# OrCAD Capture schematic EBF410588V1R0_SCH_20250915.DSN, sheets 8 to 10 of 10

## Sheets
8 10 HDMI2.1/DSI PORT: size A3; note: HDMI2.1/DSI PORT
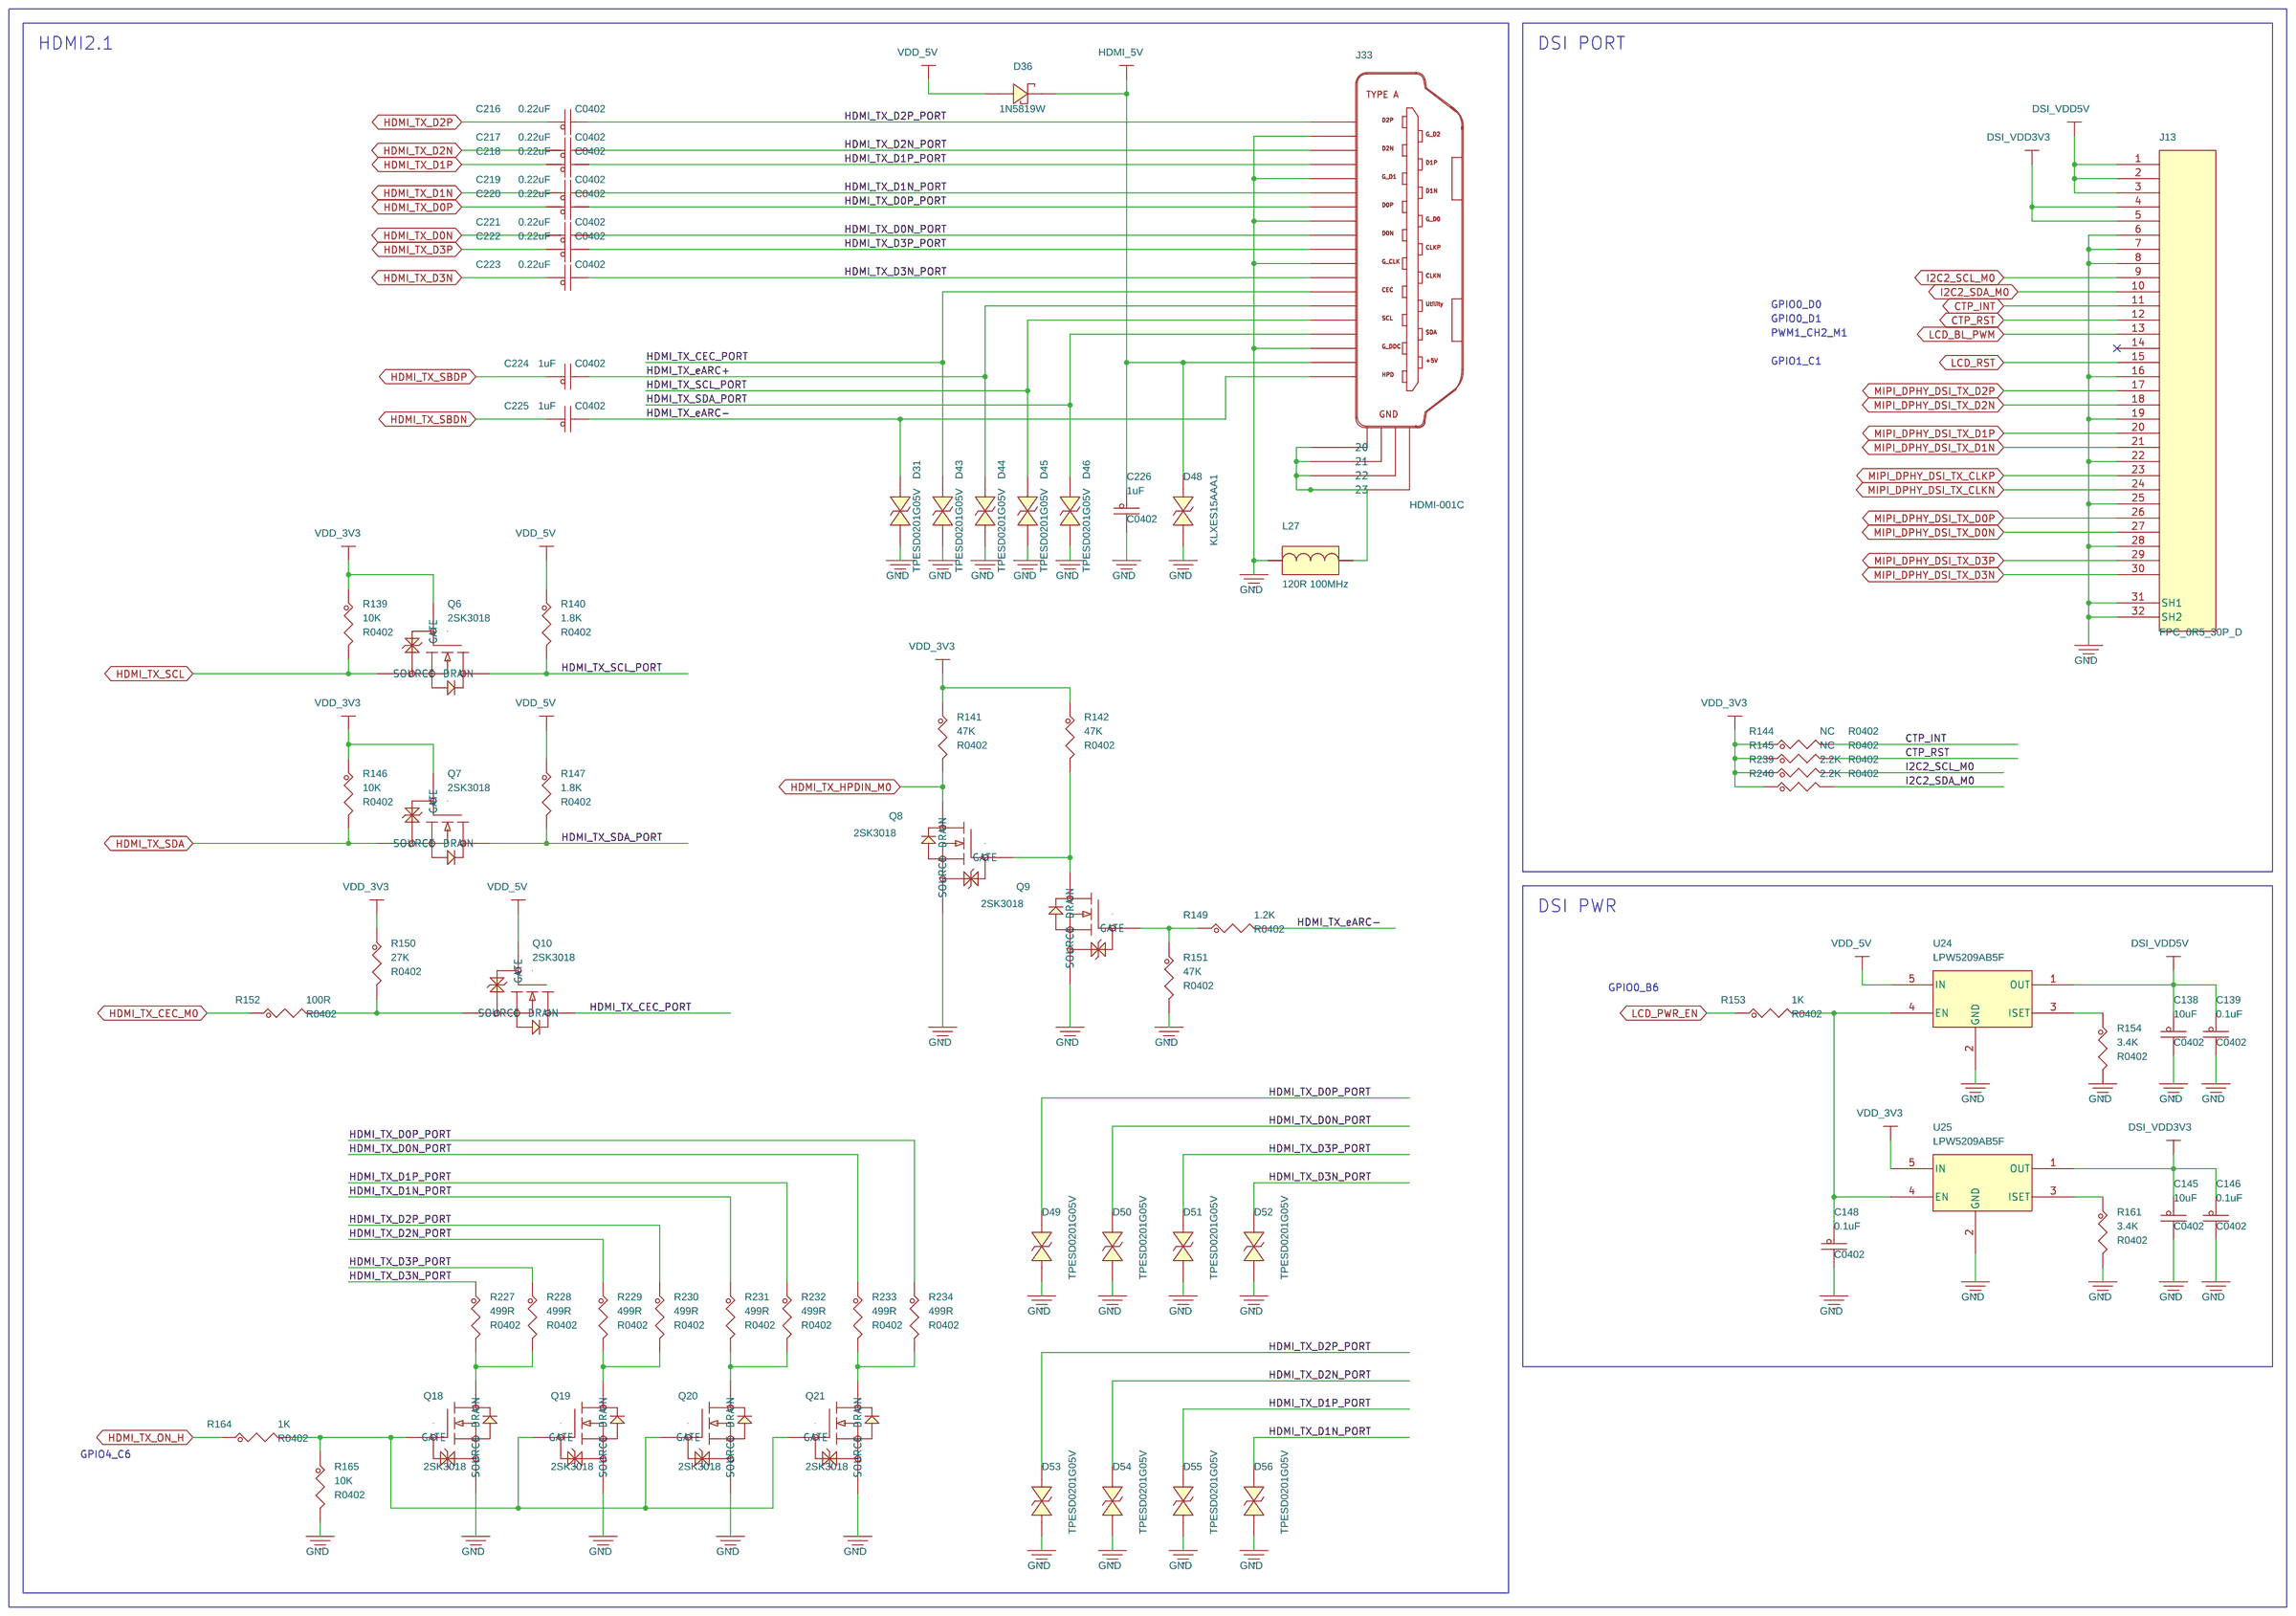
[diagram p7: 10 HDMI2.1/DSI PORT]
9 05 SD Card/RTC/KEY/IR: size A4; note: SD Card/RTC/KEY/IR
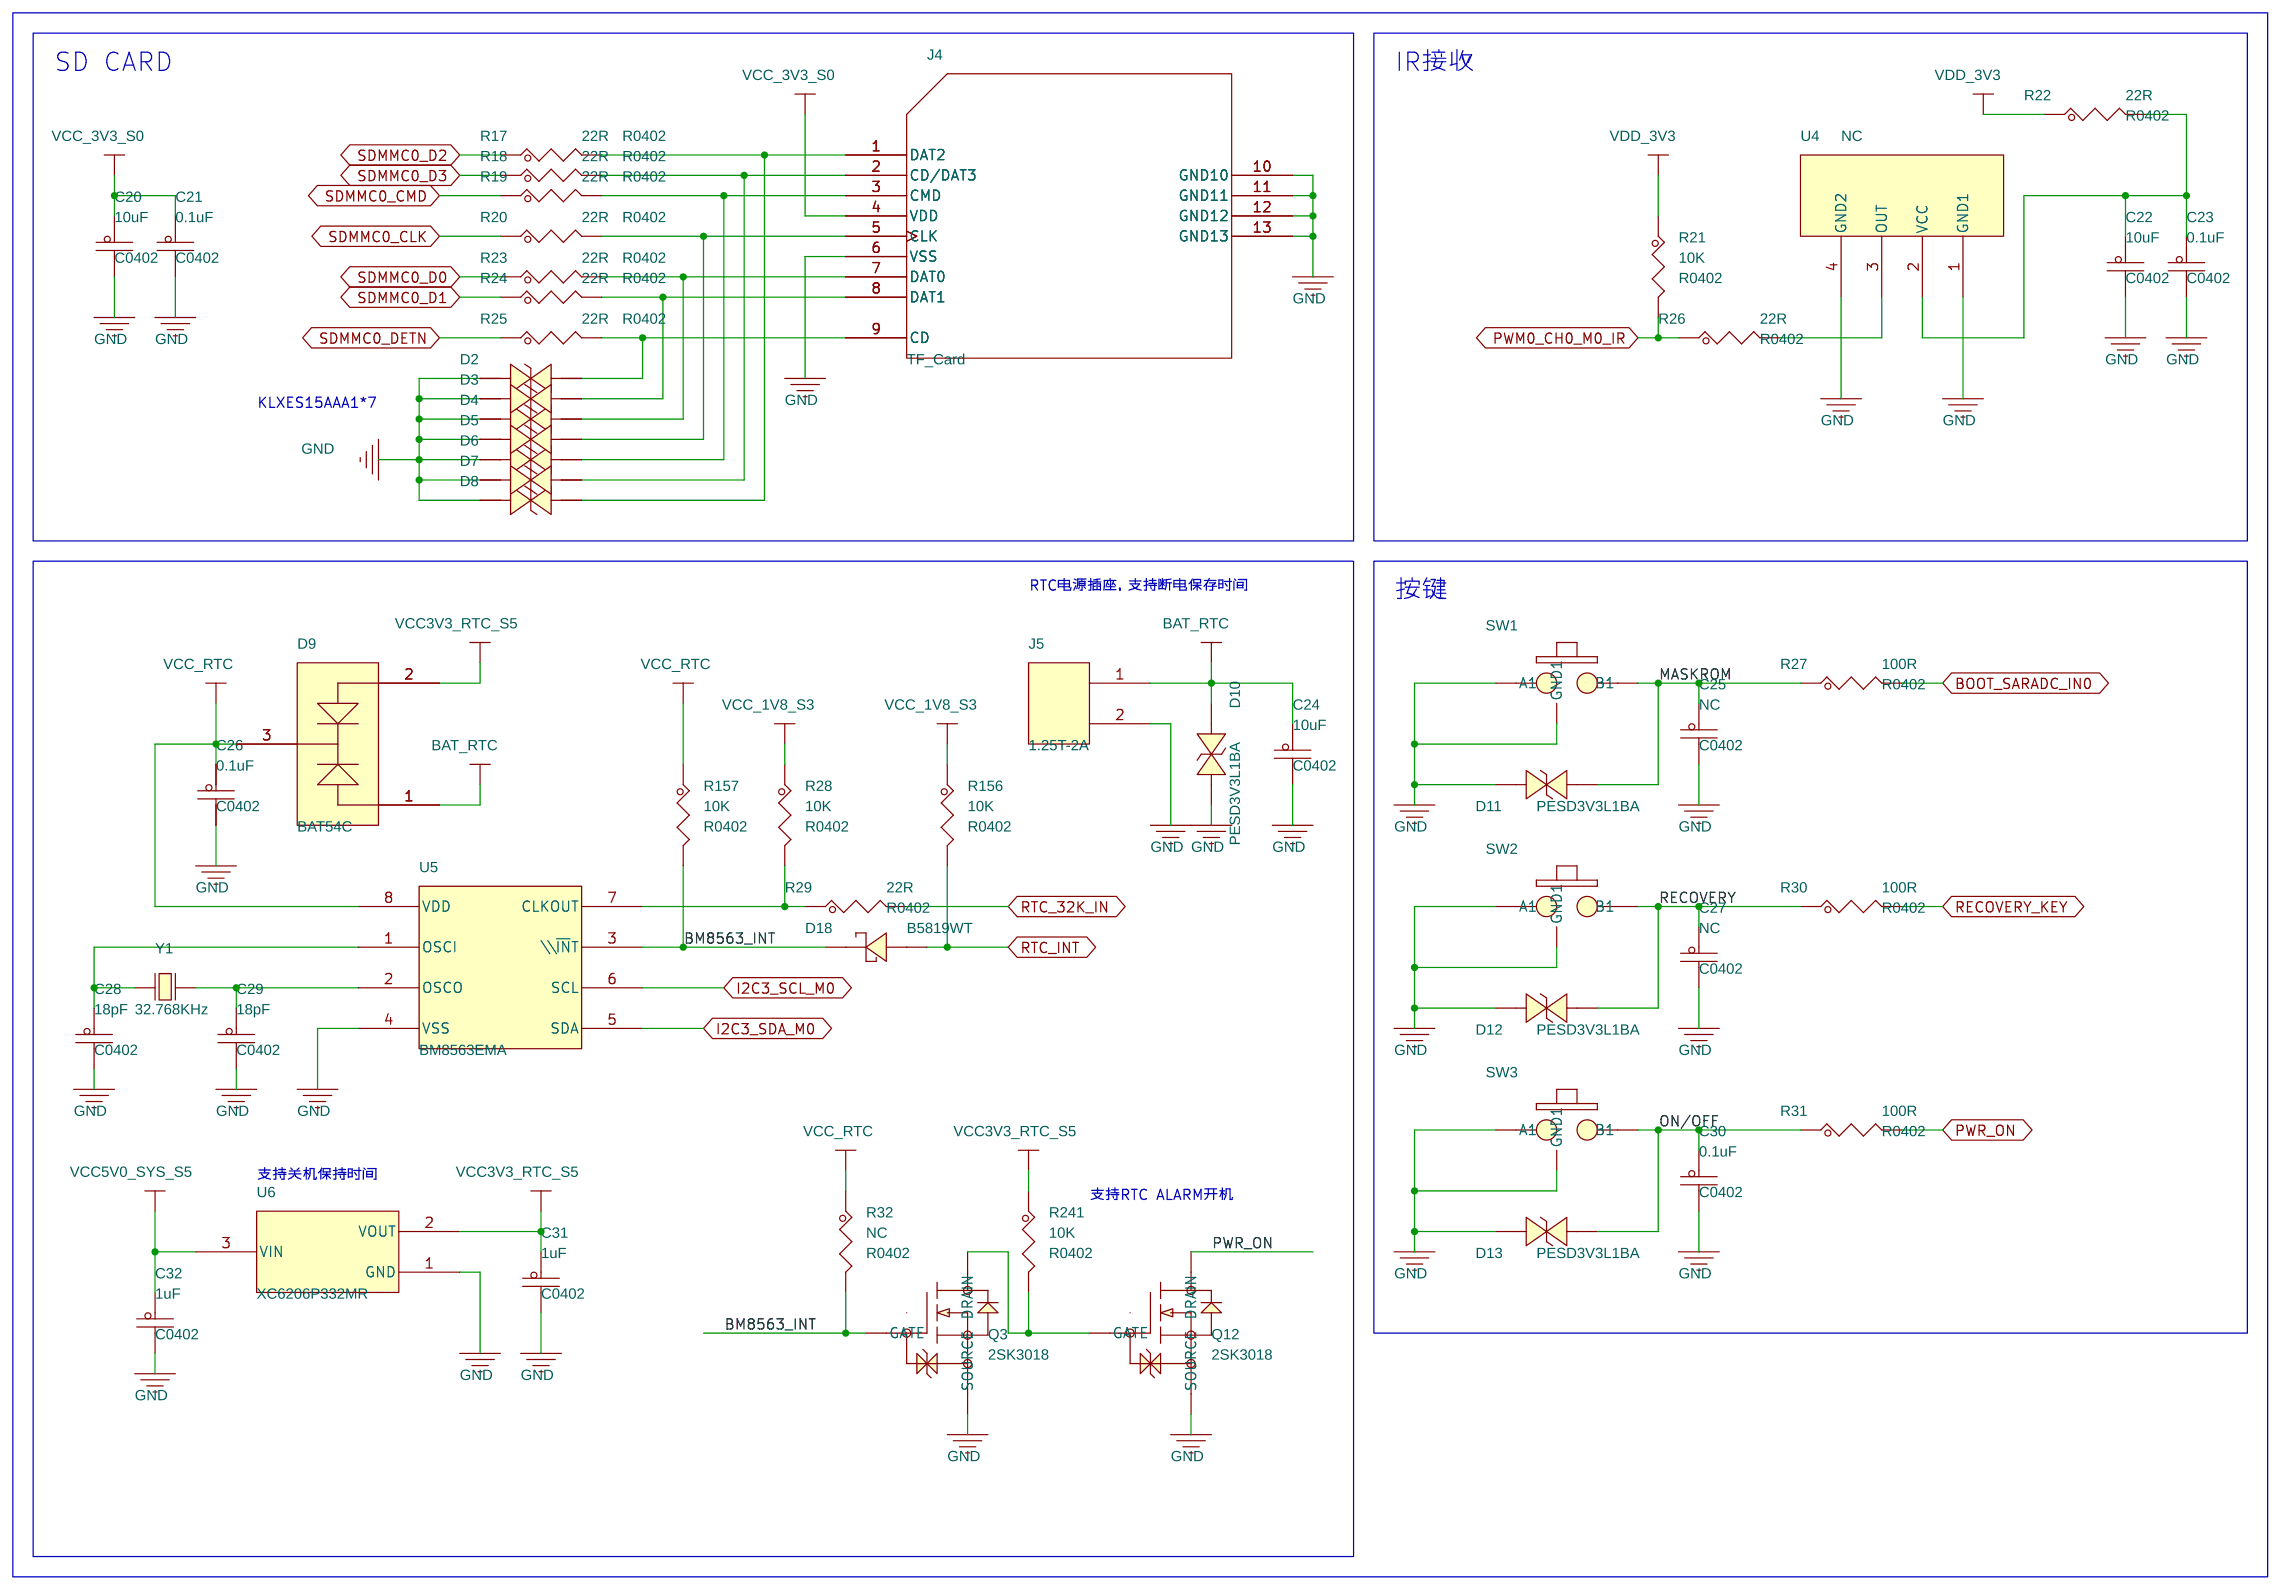
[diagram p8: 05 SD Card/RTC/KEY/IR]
10 09 USB3.0/USB2.0/TYPEC: size A3; note: USB3.0/USB2.0/TYPEC

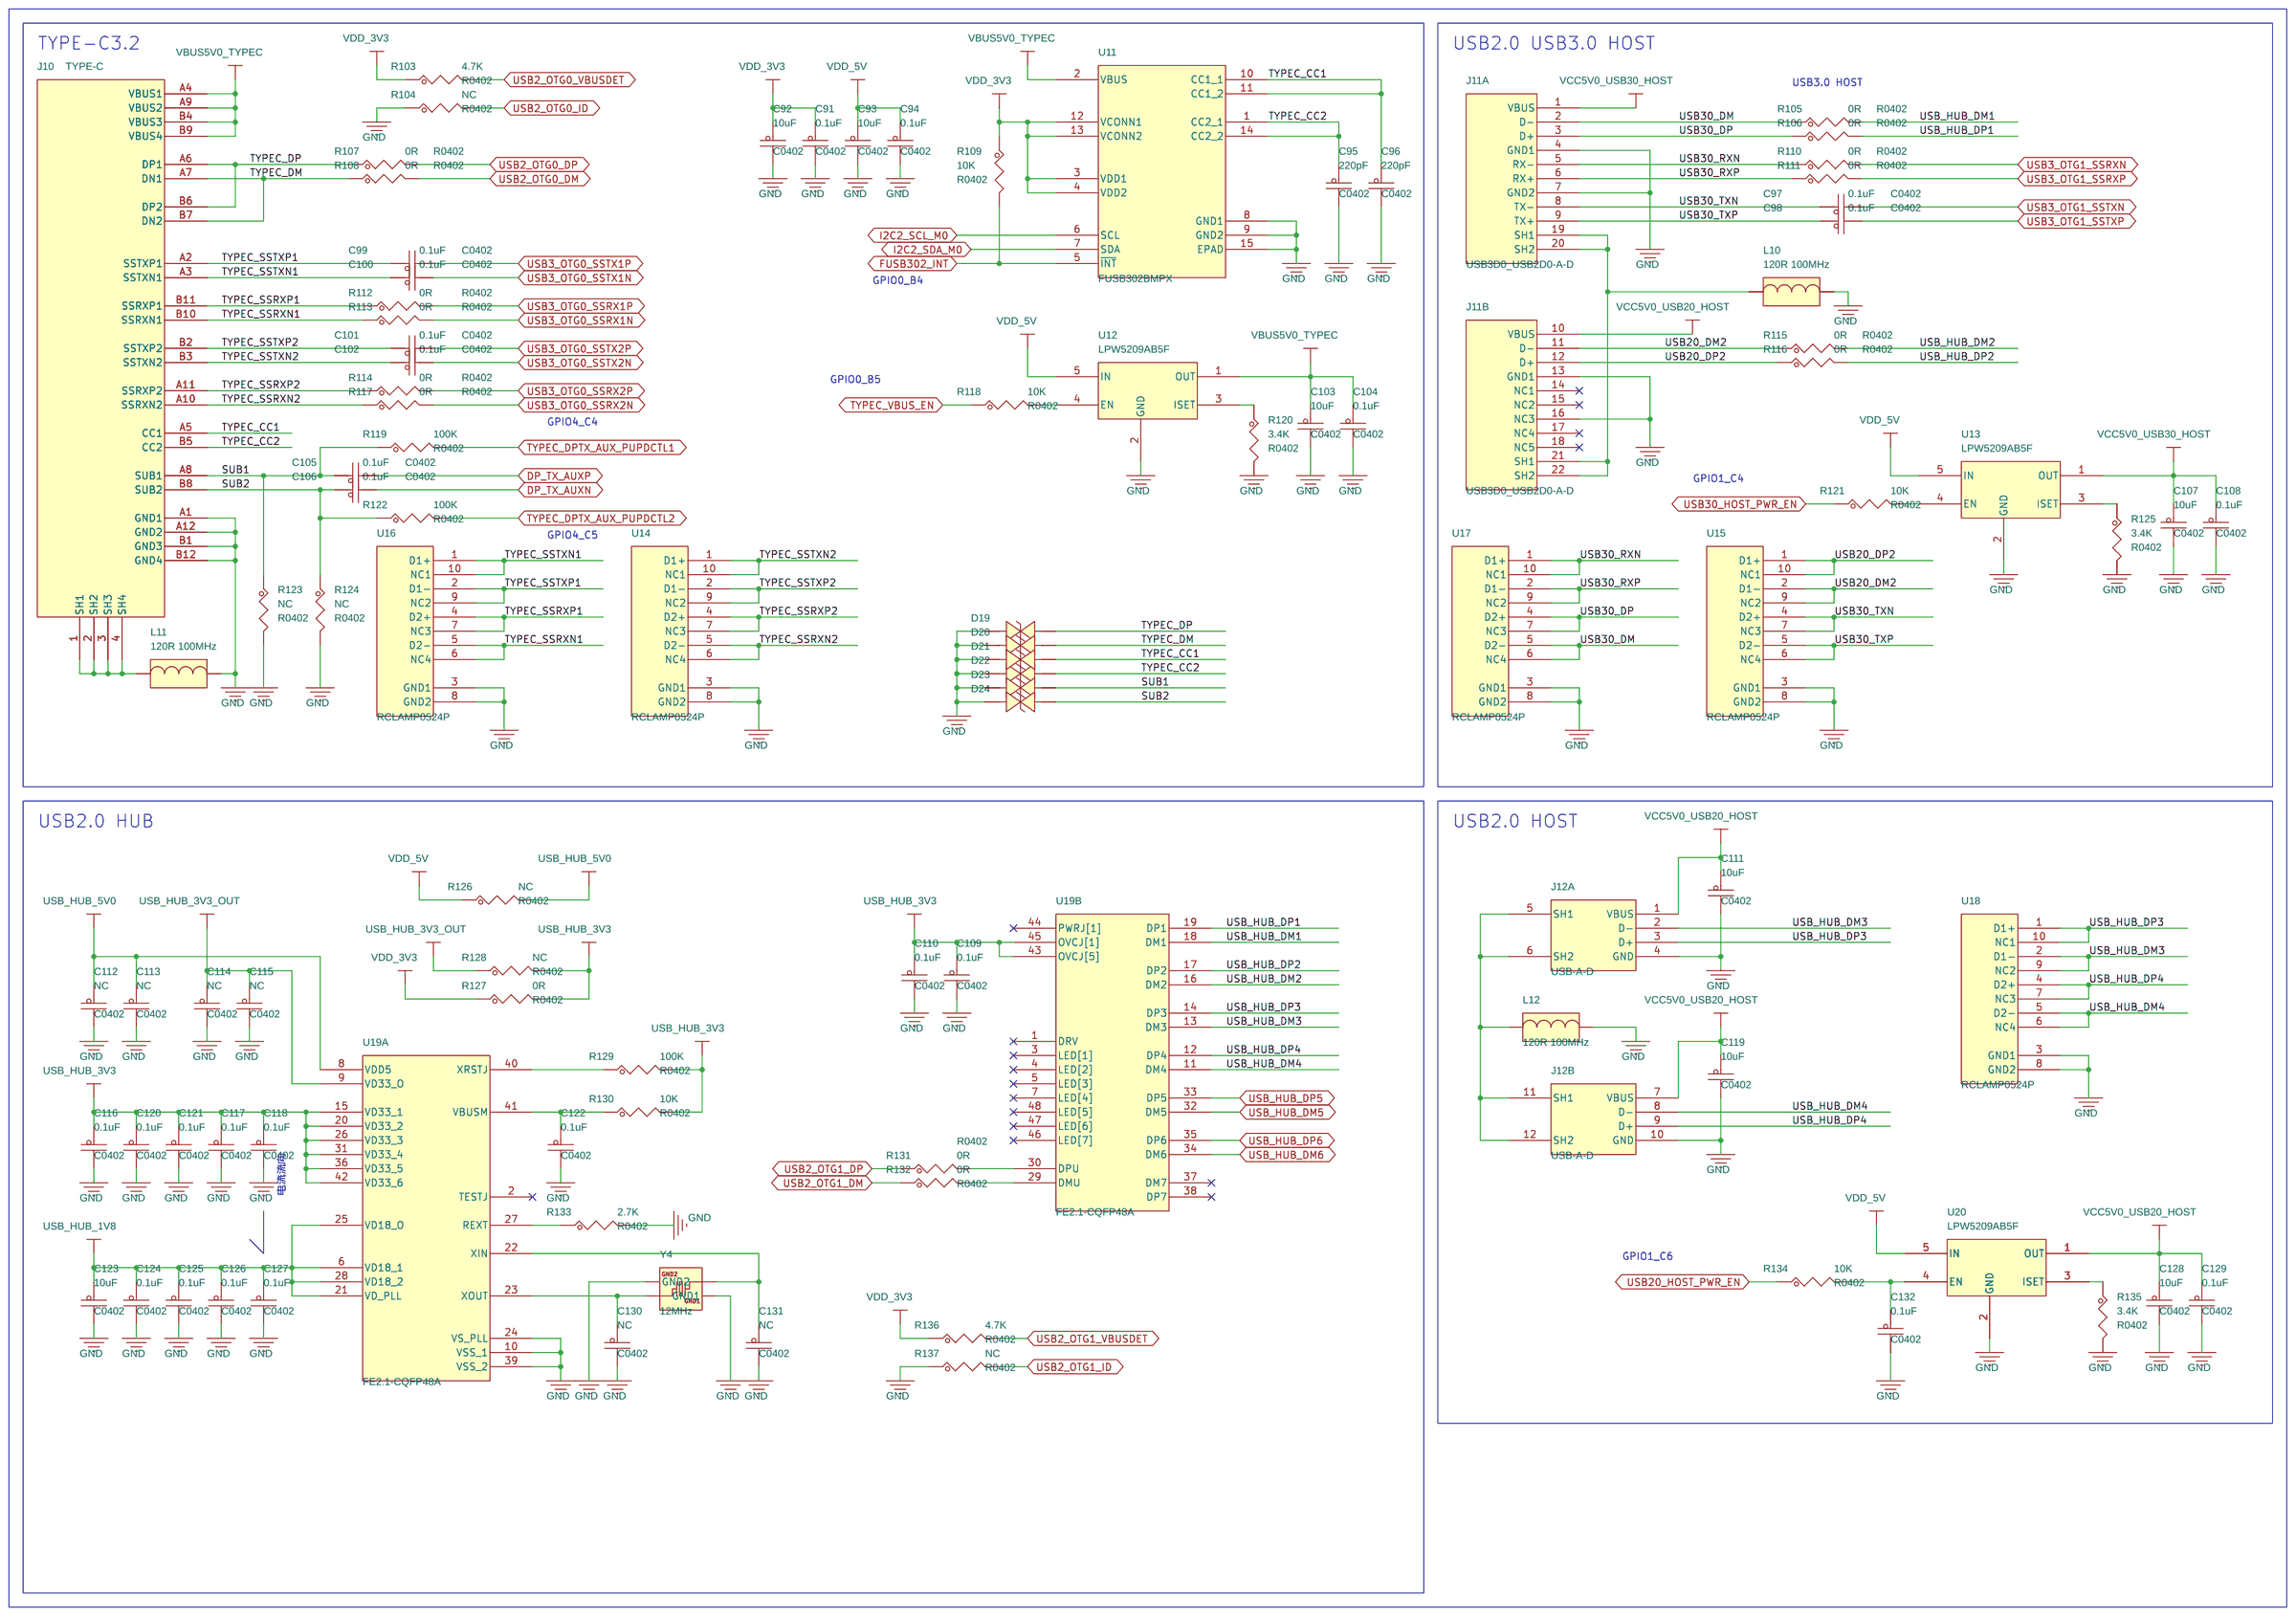
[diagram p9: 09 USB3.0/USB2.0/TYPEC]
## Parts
sheet 05 SD Card/RTC/KEY/IR
C20  10uF  [C0402]
C21  0.1uF  [C0402]
C22  10uF  [C0402]
C23  0.1uF  [C0402]
C24  10uF  [C0402]
C25  NC  [C0402]
C26  0.1uF  [C0402]
C27  NC  [C0402]
C28  18pF  [C0402]
C29  18pF  [C0402]
C30  0.1uF  [C0402]
C31  1uF  [C0402]
C32  1uF  [C0402]
D2  KLXES15AAA1  [ES0402]
D3  KLXES15AAA1  [ES0402]
D4  KLXES15AAA1  [ES0402]
D5  KLXES15AAA1  [ES0402]
D6  KLXES15AAA1  [ES0402]
D7  KLXES15AAA1  [ES0402]
D8  KLXES15AAA1  [ES0402]
D9  BAT54C  [SOT23]
D10  PESD3V3L1BA  [sod323_t]
D11  PESD3V3L1BA  [sod323_t]
D12  PESD3V3L1BA  [sod323_t]
D13  PESD3V3L1BA  [sod323_t]
D18  B5819WT  [sod523]
J4  TF_Card  [TFCARD]
J5  1.25T-2A  [gh1p25_th_2p]
Q3  2SK3018  [SOT23]
Q12  2SK3018  [SOT23]
R17  22R  [R0402]
R18  22R  [R0402]
R19  22R  [R0402]
R20  22R  [R0402]
R21  10K  [R0402]
R22  22R  [R0402]
R23  22R  [R0402]
R24  22R  [R0402]
R25  22R  [R0402]
R26  22R  [R0402]
R27  100R  [R0402]
R28  10K  [R0402]
R29  22R  [R0402]
R30  100R  [R0402]
R31  100R  [R0402]
R32  NC  [R0402]
R156  10K  [R0402]
R157  10K  [R0402]
R241  10K  [R0402]
SW1  TS-1091B-A7B3-D2  [sw_th3_4p5x4p5x6p5]
SW2  TS-1091B-A7B3-D2  [sw_th3_4p5x4p5x6p5]
SW3  TS-1091B-A7B3-D2  [sw_th3_4p5x4p5x6p5]
U4  NC  [SMD4-6R80X2R50]
U5  BM8563EMA  [msop-8]
U6  XC6206P332MR  [sot-23-3]
Y1  32.768KHz  [3215]
sheet 09 USB3.0/USB2.0/TYPEC
C91  0.1uF  [C0402]
C92  10uF  [C0402]
C93  10uF  [C0402]
C94  0.1uF  [C0402]
C95  220pF  [C0402]
C96  220pF  [C0402]
C97  0.1uF  [C0402]
C98  0.1uF  [C0402]
C99  0.1uF  [C0402]
C100  0.1uF  [C0402]
C101  0.1uF  [C0402]
C102  0.1uF  [C0402]
C103  10uF  [C0402]
C104  0.1uF  [C0402]
C105  0.1uF  [C0402]
C106  0.1uF  [C0402]
C107  10uF  [C0402]
C108  0.1uF  [C0402]
C109  0.1uF  [C0402]
C110  0.1uF  [C0402]
C111  10uF  [C0402]
C112  NC  [C0402]
C113  NC  [C0402]
C114  NC  [C0402]
C115  NC  [C0402]
C116  0.1uF  [C0402]
C117  0.1uF  [C0402]
C118  0.1uF  [C0402]
C119  10uF  [C0402]
C120  0.1uF  [C0402]
C121  0.1uF  [C0402]
C122  0.1uF  [C0402]
C123  10uF  [C0402]
C124  0.1uF  [C0402]
C125  0.1uF  [C0402]
C126  0.1uF  [C0402]
C127  0.1uF  [C0402]
C128  10uF  [C0402]
C129  0.1uF  [C0402]
C130  NC  [C0402]
C131  NC  [C0402]
C132  0.1uF  [C0402]
D19  KLXES15AAA1  [ES0402]
D20  KLXES15AAA1  [ES0402]
D21  KLXES15AAA1  [ES0402]
D22  KLXES15AAA1  [ES0402]
D23  KLXES15AAA1  [ES0402]
D24  KLXES15AAA1  [ES0402]
J10  TYPE-C  [usb-c-smd_tyc-324g]
J11  USB3D0_USB2D0-A-D  [USB3D0-AF-18P]  (sections A,B)
J12  USB-A-D  [USB-A-D]  (sections A,B)
L10  120R 100MHz  [L0402]
L11  120R 100MHz  [L0402]
L12  120R 100MHz  [L0402]
R103  4.7K  [R0402]
R104  NC  [R0402]
R105  0R  [R0402]
R106  0R  [R0402]
R107  0R  [R0402]
R108  0R  [R0402]
R109  10K  [R0402]
R110  0R  [R0402]
R111  0R  [R0402]
R112  0R  [R0402]
R113  0R  [R0402]
R114  0R  [R0402]
R115  0R  [R0402]
R116  0R  [R0402]
R117  0R  [R0402]
R118  10K  [R0402]
R119  100K  [R0402]
R120  3.4K  [R0402]
R121  10K  [R0402]
R122  100K  [R0402]
R123  NC  [R0402]
R124  NC  [R0402]
R125  3.4K  [R0402]
R126  NC  [R0402]
R127  0R  [R0402]
R128  NC  [R0402]
R129  100K  [R0402]
R130  10K  [R0402]
R131  0R  [R0402]
R132  0R  [R0402]
R133  2.7K  [R0402]
R134  10K  [R0402]
R135  3.4K  [R0402]
R136  4.7K  [R0402]
R137  NC  [R0402]
U11  FUSB302BMPX  [WQFN14-0R50-2R5X2R5EP1R45X1R45]
U12  LPW5209AB5F  [SOT23-5]
U13  LPW5209AB5F  [SOT23-5]
U14  RCLAMP0524P  [USON_10]
U15  RCLAMP0524P  [USON_10]
U16  RCLAMP0524P  [USON_10]
U17  RCLAMP0524P  [USON_10]
U18  RCLAMP0524P  [USON_10]
U19  FE2.1-CQFP48A  [LQFP48_0p5_7x7]  (sections A,B)
U20  LPW5209AB5F  [SOT23-5]
Y4  12MHz  [3225]
sheet 10 HDMI2.1/DSI PORT
C138  10uF  [C0402]
C139  0.1uF  [C0402]
C145  10uF  [C0402]
C146  0.1uF  [C0402]
C148  0.1uF  [C0402]
C216  0.22uF  [C0402]
C217  0.22uF  [C0402]
C218  0.22uF  [C0402]
C219  0.22uF  [C0402]
C220  0.22uF  [C0402]
C221  0.22uF  [C0402]
C222  0.22uF  [C0402]
C223  0.22uF  [C0402]
C224  1uF  [C0402]
C225  1uF  [C0402]
C226  1uF  [C0402]
D31  TPESD0201G05V  [R0201]
D36  1N5819W  [SOD-123]
D43  TPESD0201G05V  [R0201]
D44  TPESD0201G05V  [R0201]
D45  TPESD0201G05V  [R0201]
D46  TPESD0201G05V  [R0201]
D48  KLXES15AAA1  [ES0402]
D49  TPESD0201G05V  [R0201]
D50  TPESD0201G05V  [R0201]
D51  TPESD0201G05V  [R0201]
D52  TPESD0201G05V  [R0201]
D53  TPESD0201G05V  [R0201]
D54  TPESD0201G05V  [R0201]
D55  TPESD0201G05V  [R0201]
D56  TPESD0201G05V  [R0201]
J13  FPC_0R5_30P_D  [FPC-30P-0P5]
J33  HDMI-001C  [HDMI-SMD]
L27  120R 100MHz  [L0402]
Q6  2SK3018  [SOT23]
Q7  2SK3018  [SOT23]
Q8  2SK3018  [SOT23]
Q9  2SK3018  [SOT23]
Q10  2SK3018  [SOT23]
Q18  2SK3018  [SOT23]
Q19  2SK3018  [SOT23]
Q20  2SK3018  [SOT23]
Q21  2SK3018  [SOT23]
R139  10K  [R0402]
R140  1.8K  [R0402]
R141  47K  [R0402]
R142  47K  [R0402]
R144  NC  [R0402]
R145  NC  [R0402]
R146  10K  [R0402]
R147  1.8K  [R0402]
R149  1.2K  [R0402]
R150  27K  [R0402]
R151  47K  [R0402]
R152  100R  [R0402]
R153  1K  [R0402]
R154  3.4K  [R0402]
R161  3.4K  [R0402]
R164  1K  [R0402]
R165  10K  [R0402]
R227  499R  [R0402]
R228  499R  [R0402]
R229  499R  [R0402]
R230  499R  [R0402]
R231  499R  [R0402]
R232  499R  [R0402]
R233  499R  [R0402]
R234  499R  [R0402]
R239  2.2K  [R0402]
R240  2.2K  [R0402]
U24  LPW5209AB5F  [SOT23-5]
U25  LPW5209AB5F  [SOT23-5]

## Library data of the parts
C20 C22 C24 C92 C93 C103 C107 C111 C119 C123 C128 C138 C145 = CAP_NP: voltage: 10V; 规格: 贴片电容10uF 20% 10V X5R 0402; 规格编号: CL05A106MP8NUB8; 规格书: 三星电容.pdf; 价格: 0.518415; 类别: 贴片电容0402; 品牌: 三星; 生命周期: 量产; 条码: EBF29060247
C21 C23 C26 C30 C91 C94 C97-C102 C104-C106 C108-C110 C116-C118 C120-C122 C124-C127 C129 C132 C139 C146 C148 = CAP_NP: voltage: 50V; 规格: 贴片电容0.1uF 10% 50V X5R 0402; 规格编号: 0402X104K500NT; 规格书: 风华电容.pdf; 价格: 0.029826; 类别: 贴片电容0402; 品牌: 风华; 生命周期: 量产; 条码: EBF29060118
C25 C27 C112-C115 C130 C131 = CAP_NP: 规格: 贴片电容NC 预留; 类别: 贴片电容0402; 条码: EBF29060149
C28 C29 = CAP_NP: voltage: 50V; 规格: 贴片电容18pF 5% 50V C0G 0402; 规格编号: 0402CG180J500NT; 规格书: 风华电容.pdf; 价格: 0.00515; 类别: 贴片电容0402; 品牌: 风华; 生命周期: 量产; 条码: EBF29060235
C31 C32 C224-C226 = CAP_NP: voltage: 10V; 规格: 贴片电容1uF 10% 10V X5R 0402; 规格编号: 0402X105K100NT; 规格书: 风华电容.pdf; 价格: 0.01191; 类别: 贴片电容0402; 品牌: 风华; 生命周期: 量产; 条码: EBF29060121
D2-D8 D19-D24 D48 = DIODE_BI-DIR_TRIG: 规格: 用于 USB3.0、HDMI 0.5pF、5V、±15kV ESD 保护二极管; 规格书: KLXES15AAA1.pdf; 价格: 0.09719; 类别: 贴片ESD; 品牌: 永裕泰; 生命周期: 量产; 条码: EBF29140063
D9 = BAT54C: 规格: 肖特基双二极管 直流反向耐压(Vr) 30V 平均整流电流(Io) 300mA 正向压降(Vf) 1V@100mA; 规格书: 江苏长电_BAT54C.pdf; 价格: 0.077486; 类别: 贴片肖特基二极管; 品牌: 江苏长电; 生命周期: 量产; 丝印: KL3; 条码: EBF29140062
D10-D13 = DIODE_BI-DIR_TRIG: 规格: 防静电保护ESD二极管 箝位电压26V 击穿电压5.8V 反向关断电压3.3V; 规格编号: PESD3V3L1BA 115; 规格书: 安世-PESD3V3L1BA-115.pdf; 价格: 0.31497; 类别: 贴片ESD; 品牌: 安世; 生命周期: 量产; 丝印: AB; 条码: EBF29140003
D18 = DIODE_SCHTKY: 规格: 肖特基二极管 直流反向耐压:40V 平均整流电流:350mA 正向压降:600mV@200mA 封装：SOD 523; 规格书: B5819WT.pdf; 价格: 0.086188; 类别: 贴片肖特基二极管; 品牌: 萨科微; 生命周期: 量产; 条码: EBF29140061
J4 = TF_Card: 规格: MICRO SD 卡座 TF T-Flash 外焊 双压片 自弹贴片; 规格编号: TF-015; 规格书: 硕方-TF-015.pdf; 价格: 0.48; 可替代料: EBF29040003; 类别: SD卡连接器; 品牌: 硕方; 生命周期: 量产; 条码: EBF29040003
J5 = 1X2PIN: 规格: 间距=1.25mm 直插 2P针座连接器; 规格书: 1.25T-2A.pdf; 类别: 1.25连接器; 品牌: 创都; 生命周期: 量产; 条码: EBF29040105
Q3 Q6-Q10 Q12 Q18-Q21 = 2SK3018: 规格: N沟道MOS 导通电阻8Ω 电流10mA 0.8V可驱动; 规格书: 长电科技-2SK3018.pdf; 价格: 0.120725; 类别: N-MOS; 品牌: 江苏长电; 生命周期: 量产; 丝印: KN; 条码: EBF29280009
R17-R20 R22-R26 R29 = RES: 规格: 贴片电阻22R 1% 1/16W 0402; 规格编号: RI0402L22R0FT; 规格书: 合科泰-RI系列电阻.pdf; 类别: 贴片电阻0402; 品牌: 合科泰; 生命周期: 量产; 条码: EBF29070181
R21 R28 R109 R118 R121 R130 R134 R139 R146 R156 R157 R165 R241 = RES: 规格: 贴片电阻10K 1% 1/16W 0402; 规格编号: 0402WGF1002TCE; 规格书: 厚声-无铅厚膜电阻.pdf; 价格: 0.002773; 类别: 贴片电阻0402; 品牌: 厚声; 生命周期: 量产; 条码: EBF29070046
R27 R30 R31 R152 = RES: 规格: 贴片电阻100R 1% 1/16W 0402; 规格编号: RI0402L1000FT; 规格书: 合科泰-RI系列电阻.pdf; 类别: 贴片电阻0402; 品牌: 合科泰; 生命周期: 量产; 条码: EBF29070053
R32 R104 R123 R124 R126 R128 R137 R144 R145 = RES: 规格: 贴片电阻NC 预留; 类别: 贴片电阻0402; 条码: EBF29070087
SW1-SW3 = SW_TH3P: 规格: 轻触开关4.5*4.5*6.5边三脚侧插侧按按键; 规格书: C557913_轻触开关4.5_4.5_6.5边三脚侧插侧按按键256GF_2020-05-22.pdf; 价格: 0.220608; 类别: 直插按键; 品牌: 台湾元迪; 生命周期: 量产; 条码: EBF29310015
U4 = IRM-V838M3-C_TR1: 规格: 侧贴红外遥控接收头 工作电压2.7V~5.5V 兼容TTL与CMOS; 规格编号: IRM-V838M3-C/TR1; 规格书: IRM-V838M3-C_TR1.pdf; 类别: 红外接收头; 品牌: 亿光; 生命周期: 量产
U5 = HYM8563S: 备注: 鲁班猫系列板子; 规格: 工作电压1.5V~5.5V 日期格式YY-MM-DD 时间格式HH:MM:SS 接口类型I2C 电流消耗0.25uA~@3.0V; 规格书: 捷茂微_BM8563EMA.pdf; 价格: 0.8789; 类别: 实时时钟芯片; 品牌: 捷茂微; 生命周期: 量产; 条码: EBFCIS240229100017
U6 = LDO-3P: 备注: 野火小智; 规格: 低压差LDO 最高8V 输出3.3V 最大电流250mA 压差300mV 工作温度-45-85℃  纹波抑制比40db; 规格书: UWM_XC6206P332MR.pdf; 价格: 0.054; 类别: 电源管理-LDO; 品牌: 友台半导体; 生命周期: 量产; 丝印: SS2K; 条码: EBFCIS231202145047
Y1 = CRYSTAL_2P: 备注: 国产晶振，可替换爱普生32.768K无源晶振; 规格: 无源晶振32.768KHz 等效电阻：70KΩ 负载电容：12.5pf  SMD_3215; 规格书: 鑫亿晶_32.768KHz.pdf; 类别: 贴片晶振 3215; 品牌: 鑫亿晶; 生命周期: 量产; 丝印: X2A20A; 条码: EBFCIS231207112230
C95 C96 = CAP_NP: voltage: 50V; 规格: 贴片电容220pF 10% 50V X7R 0402; 规格编号: 0402B221K500NT; 规格书: 风华电容.pdf; 价格: 0.00358; 类别: 贴片电容0402; 品牌: 风华; 条码: EBFCIS221112143723
J10 = TYPE-C-24P: 规格: Type-C母座 24P USB-3.1 插座 4固定脚 双向; 规格编号: TYC-324G; 规格书: 讯普_TYC-324G.pdf; 类别: USB接口; 品牌: 讯普; 条码: EBFCIS220922094113
J11 = USB3D0_USB2D0-A-D: 规格: USB3.0_USB2.0母座; 规格编号: UEA1112C-UHS6-4F; 规格书: UEA1112C-UHS6-4F.pdf; 类别: USB接口; 品牌: 富士康; 生命周期: 量产; 条码: EBF29040092
J12 = USB-A-D: 规格: 双层USB接口 A型接口 90度双排弯插脚 AF母座 焊接式; 规格编号: 907-111A1012D10200; 规格书: 精拓金-双层USB.pdf; 价格: 0.22; 类别: USB接口; 品牌: 精拓金; 生命周期: 量产; 条码: EBF29020027
L10-L12 L27 = BEAD: 规格: 磁珠120Ω @100MHz 额定电流1A 直流电阻120mΩ; 规格编号: PZ1005U121-1R0TF; 规格书: 顺络-磁珠120Ω±25%100MHZ.pdf; 价格: 0.020259; 类别: 贴片磁珠0402; 品牌: 顺络; 生命周期: 量产; 条码: EBF29050044
R103 R136 = RES: 规格: 贴片电阻4.7K 1% 1/16W 0402; 规格编号: RI0402L4701FT; 规格书: 合科泰-RI系列电阻.pdf; 类别: 贴片电阻0402; 品牌: 合科泰; 生命周期: 量产; 条码: EBF29070047
R105-R108 R110-R117 R127 R131 R132 = RES: 规格: 贴片电阻0R 1% 1/16W 0402; 规格编号: RI0402L000FT; 规格书: 合科泰-RI系列电阻.pdf; 类别: 贴片电阻0402; 品牌: 合科泰; 生命周期: 量产; 条码: EBF29070049
R119 R122 R129 = RES: 规格: 贴片电阻100K 1% 1/16W 0402; 规格编号: RI0402L1003FT; 规格书: 合科泰-RI系列电阻.pdf; 类别: 贴片电阻0402; 品牌: 合科泰; 生命周期: 量产; 条码: EBF29070054
R120 R125 R135 R154 R161 = RES: 规格: 贴片电阻3.4K 1% 1/16W 0402; 规格编号: RI0402L3401FT; 规格书: 合科泰-RI系列电阻.pdf; 类别: 贴片电阻0402; 品牌: 合科泰; 生命周期: 量产; 条码: EBF29070186
R133 = RES: 规格: 贴片电阻2.7K 1% 1/16W 0402; 规格编号: RMC04022.7K1%N; 规格书: 幸亚电阻.pdf; 价格: 0.016497; 类别: 贴片电阻0402; 品牌: 幸亚; 生命周期: 量产; 条码: EBF29070202
U11 = FUSB302BMPX: 规格: 可编程USB Type-C控制器 支持USB Type-C检测 带PD 可实现高达 100 W 的电源和角色互换; 规格书: 安森美_FUSB302BMPX.pdf; 价格: 3.8016; 类别: USB芯片; 品牌: 安森美; 生命周期: 量产; 条码: EBFCIS221116112239
U12 U13 U20 U24 U25 = LPW5209AB5F: 规格: 集成电源开关 导通电阻：80mΩ 最大可设置保护电流：2.1A 输入电压：2.5V~6V 静态电流：30uA 其他功能：软启动、短路保护、热保护; 规格书: 微源半导体_LPW5209AB5F.pdf; 价格: 0.468063; 类别: 功率开关; 品牌: 微源半导体; 生命周期: 量产; 条码: EBF29280015
U14-U18 = RCLAMP0524P: 规格: TVS二极管 箝位电压17V 击穿电压8V 反向关断电压5V; 规格书: 台舟-RCLAMP0524P.pdf; 价格: 0.185957; 类别: 贴片四路ESD; 品牌: 台舟; 生命周期: 量产; 条码: EBF29140046
U19 = FE2.1-CQFP48A: 备注: RK3576 LBC3; 规格: USB HUB芯片 工作电压3.3V 5V 协议类别USB2.0 支持高速(480Mbps) 全速(12Mbps)和低速(1.5Mbps)模式 一扩展七; 规格书: 汤铭科技_FE2.1-CQFP48A.pdf; 库存: 5.5; 类别: USB芯片; 品牌: 汤铭科技; 生命周期: 量产; 条码: EBFCIS240517170505
Y4 = CRYSTAL_4P: 备注: 通用; 规格: 无源晶振12MHZ ±10ppm 80Ω 20pF -20℃~+70℃ 3225; 规格编号: RL3225-12M; 规格书: 创捷_3225贴片晶振.pdf; 类别: 贴片晶振 3225; 品牌: 创捷; 生命周期: 量产; 条码: EBFCIS241228135855
C216-C223 = CAP_NP: voltage: 25V; 备注: 新增0402物料; 规格: 贴片电容0.22uF 20% 25V X7R 0402; 规格编号: TCC0402X7R224K250AT; 规格书: CCTC_TCC0402X5R105K6R3AT; 价格: 0.0073; 类别: 贴片电容0402; 品牌: CCTC; 生命周期: 量产; 条码: EBFCIS241220094109
D31 D43-D46 D49-D56 = DIODE_BI-DIR_TRIG: 备注: RK3588S LBC4; 规格: 防静电保护ESD二极管 ±15kV 0.05pF 用于USB3.0/3.1 HDMI1.3/1.4/2.0; 规格书: 台舟ESD_TPESD0201G系列规格书.pdf; 价格: 0.118206; 类别: 贴片ESD; 品牌: 台舟; 生命周期: 量产; 条码: EBFCIS230829005342
D36 = DIODE_SCHTKY: 规格: 肖特基二极管 直流反向耐压40V 平均整流电流1A 正向压降0.6V@1A SOD-123; 规格书: 1N5819W.pdf; 价格: 0.175675; 类别: 贴片肖特基二极管; 品牌: 台湾迪嘉; 生命周期: 量产; 丝印: SL; 条码: EBF29140016
J13 = FPC-30P: 规格: FPC连接器 针脚数30 间距0.5mm 高度2.0mm 下接 卧贴 翻盖式; 规格编号: FPC-05F-30PH20; 规格书: FPC-05F-NPH20.pdf; 类别: FPC连接器; 品牌: 讯普; 生命周期: 量产; 条码: EBF29040079
J33 = HDMI-001C: 规格: HDMI立式; 规格书: HDMI-001C.pdf; 类别: HDMI连接器; 品牌: 讯普; 生命周期: 量产; 条码: EBF29040081
R140 R147 = RES: 规格: 贴片电阻1.8K 1% 1/16W 0402; 规格编号: 0402WGF1801TCE; 规格书: 厚声-无铅厚膜电阻.pdf; 价格: 0.00212; 类别: 贴片电阻0402; 品牌: 厚声; 生命周期: 量产; 条码: EBFCIS221112110749
R141 R142 R151 = RES: 规格: 贴片电阻47K 1% 1/16W 0402; 规格编号: 0402WGF4702TCE; 规格书: 厚声-无铅厚膜电阻.pdf; 类别: 贴片电阻0402; 品牌: 厚声; 生命周期: 量产; 条码: EBF29070247
R149 = RES: 规格: 贴片电阻1.2K 1% 1/16W 0402; 规格编号: 0402WGF1201TCE; 规格书: 厚声-无铅厚膜电阻.pdf; 价格: 0.001447; 类别: 贴片电阻0402; 品牌: 厚声; 生命周期: 量产; 条码: EBFCIS221112112140
R150 = RES: 规格: 贴片电阻27K 1% 1/16W 0402; 规格编号: AC0402FR-0727KL; 规格书: YAGEO国巨厚膜无铅电阻.pdf; 价格: 0.007054; 类别: 贴片电阻0402; 品牌: 国巨; 生命周期: 量产; 条码: EBF29070003
R153 R164 = RES: 规格: 贴片电阻1K 1% 1/16W 0402; 规格编号: RI0402L1001FT; 规格书: 合科泰-RI系列电阻.pdf; 类别: 贴片电阻0402; 品牌: 合科泰; 生命周期: 量产; 条码: EBF29070050
R227-R234 = RES: 规格: 贴片电阻499R 1% 1/16W 0402; 规格编号: 0402WGF4990TCE; 规格书: 厚声-无铅厚膜电阻.pdf; 价格: 0.003791; 类别: 贴片电阻0402; 品牌: 厚声; 生命周期: 量产; 条码: EBF29070287
R239 R240 = RES: 规格: 贴片电阻2.2K 1% 1/16W 0402; 规格编号: RI0402L2201FT; 规格书: 合科泰-RI系列电阻.pdf; 类别: 贴片电阻0402; 品牌: 合科泰; 生命周期: 量产; 条码: EBF29070051

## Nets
GND: C20.2 C21.2 C22.2 C23.2 C24.2 C25.2 C26.2 C27.2 C28.2 C29.2 C30.2 C31.2 C32.2 C91.2 C92.2 C93.2 C94.2 C95.2 C96.2 C103.2 C104.2 C107.2 C108.2 C109.2 C110.2 C111.2 C112.2 C113.2 C114.2 C115.2 C116.2 C117.2 C118.2 C119.2 C120.2 C121.2 C122.2 C123.2 C124.2 C125.2 C126.2 C127.2 C128.2 C129.2 C130.2 C131.2 C132.2 C138.2 C139.2 C145.2 C146.2 C148.2 C226.2 D2.1 D3.1 D4.1 D5.1 D6.1 D7.1 D8.1 D10.1 D11.1 D12.1 D13.1 D19.1 D20.1 D21.1 D22.1 D23.1 D24.1 D31.1 D43.1 D44.1 D45.1 D46.1 D48.2 D49.1 D50.1 D51.1 D52.1 D53.1 D54.1 D55.1 D56.1 J4.6(VSS) J4.10(GND10) J4.11(GND11) J4.12(GND12) J4.13(GND13) J5.2 J10.A1(GND1) J10.A12(GND2) J10.B1(GND3) J10.B12(GND4) J11.4(GND1) J11.7(GND2) J11.13(GND1) J11.16(NC3) J12.4(GND) J12.10(GND) J13.6 J13.7 J13.8 J13.16 J13.19 J13.22 J13.25 J13.28 J13.31(SH1) J13.32(SH2) J33.2 J33.5 J33.8 J33.11 J33.17 L10.2 L11.2 L12.2 L27.1 Q3.2(SOURCE) Q8.2(SOURCE) Q9.2(SOURCE) Q12.2(SOURCE) Q18.2(SOURCE) Q19.2(SOURCE) Q20.2(SOURCE) Q21.2(SOURCE) R104.1 R120.2 R123.2 R124.2 R125.2 R133.2 R135.2 R137.1 R151.2 R154.2 R161.2 R165.2 SW1.1(A1) SW1.3(GND1) SW2.1(A1) SW2.3(GND1) SW3.1(A1) SW3.3(GND1) U4.1(GND1) U4.4(GND2) U5.4(VSS) U6.1(GND) U11.8(GND1) U11.9(GND2) U11.15(EPAD) U12.2(GND) U13.2(GND) U14.3(GND1) U14.8(GND2) U15.3(GND1) U15.8(GND2) U16.3(GND1) U16.8(GND2) U17.3(GND1) U17.8(GND2) U18.3(GND1) U18.8(GND2) U19.10(VSS_1) U19.24(VS_PLL) U19.39(VSS_2) U20.2(GND) U24.2(GND) U25.2(GND) Y4.2(GND1) Y4.4(GND2) ; also on sheet 1 2 3 4 5 6 7
VBUS5V0_TYPEC: C103.1 C104.1 J10.A4(VBUS1) J10.A9(VBUS2) J10.B4(VBUS3) J10.B9(VBUS4) U11.2(VBUS) U12.1(OUT)
VCC3V3_RTC_S5: C31.1 D9.2 R241.1 U6.2(VOUT)
VCC5V0_SYS_S5: C32.1 U6.3(VIN)
VCC5V0_USB20_HOST: C111.1 C119.1 C128.1 C129.1 J11.10(VBUS) J12.1(VBUS) J12.7(VBUS) U20.1(OUT)
VCC5V0_USB30_HOST: C107.1 C108.1 J11.1(VBUS) U13.1(OUT)
VCC_1V8_S3: R28.1 R156.1 ; also on sheet 1 2
VCC_3V3_S0: C20.1 C21.1 J4.4(VDD)
VCC_RTC: C26.1 D9.3 R32.1 R157.1 U5.8(VDD)
VDD_3V3: C91.1 C92.1 Q6.1(GATE) Q7.1(GATE) R21.1 R22.1 R103.1 R109.1 R127.1 R136.1 R139.1 R141.1 R142.1 R144.1 R145.1 R146.1 R150.1 R239.1 R240.1 U11.3(VDD1) U11.4(VDD2) U11.12(VCONN1) U11.13(VCONN2) U25.5(IN) ; also on sheet 1 2 3 5 6 7
VDD_5V: C93.1 C94.1 D36.2 Q10.1(GATE) R126.1 R140.1 R147.1 U12.5(IN) U13.5(IN) U20.5(IN) U24.5(IN) ; also on sheet 3 5 6 7
BAT_RTC: C24.1 D9.1 D10.2 J5.1
BM8563_INT: D18.1 Q3.1(GATE) R32.2 R157.2 U5.3(\\~{IN}T)
BOOT_SARADC_IN0: R27.2
CTP_INT: J13.11 R144.2
CTP_RST: J13.12 R145.2
DP_TX_AUXN: C106.2
DP_TX_AUXP: C105.2
DSI_VDD3V3: C145.1 C146.1 J13.4 J13.5 U25.1(OUT)
DSI_VDD5V: C138.1 C139.1 J13.1 J13.2 J13.3 U24.1(OUT)
FUSB302_INT: R109.2 U11.5(~{INT})
HDMI_5V: C226.1 D36.1 D48.1 J33.18
HDMI_TX_CEC_M0: R152.1
HDMI_TX_CEC_PORT: D43.2 J33.13 Q10.3(DRAIN)
HDMI_TX_D0N: C221.1
HDMI_TX_D0N_PORT: C221.2 D50.2 J33.9 R233.1
HDMI_TX_D0P: C220.1
HDMI_TX_D0P_PORT: C220.2 D49.2 J33.7 R234.1
HDMI_TX_D1N: C219.1
HDMI_TX_D1N_PORT: C219.2 D56.2 J33.6 R231.1
HDMI_TX_D1P: C218.1
HDMI_TX_D1P_PORT: C218.2 D55.2 J33.4 R232.1
HDMI_TX_D2N: C217.1
HDMI_TX_D2N_PORT: C217.2 D54.2 J33.3 R229.1
HDMI_TX_D2P: C216.1
HDMI_TX_D2P_PORT: C216.2 D53.2 J33.1 R230.1
HDMI_TX_D3N: C223.1
HDMI_TX_D3N_PORT: C223.2 D52.2 J33.12 R227.1
HDMI_TX_D3P: C222.1
HDMI_TX_D3P_PORT: C222.2 D51.2 J33.10 R228.1
HDMI_TX_eARC+: C224.2 D44.2 J33.14
HDMI_TX_eARC-: C225.2 D31.2 J33.19 R149.2
HDMI_TX_HPDIN_M0: Q8.3(DRAIN) R141.2
HDMI_TX_ON_H: R164.1
HDMI_TX_SBDN: C225.1
HDMI_TX_SBDP: C224.1
HDMI_TX_SCL: Q6.2(SOURCE) R139.2
HDMI_TX_SCL_PORT: D45.2 J33.15 Q6.3(DRAIN) R140.2
HDMI_TX_SDA: Q7.2(SOURCE) R146.2
HDMI_TX_SDA_PORT: D46.2 J33.16 Q7.3(DRAIN) R147.2
I2C2_SCL_M0: J13.9 R239.2 U11.6(SCL)
I2C2_SDA_M0: J13.10 R240.2 U11.7(SDA)
I2C3_SCL_M0: U5.6(SCL) ; also on sheet 3 6
I2C3_SDA_M0: U5.5(SDA) ; also on sheet 3 6
LCD_BL_PWM: J13.13
LCD_PWR_EN: R153.1
LCD_RST: J13.15
MASKROM: C25.1 D11.2 R27.1 SW1.2(B1)
MIPI_DPHY_DSI_TX_CLKN: J13.24
MIPI_DPHY_DSI_TX_CLKP: J13.23
MIPI_DPHY_DSI_TX_D0N: J13.27
MIPI_DPHY_DSI_TX_D0P: J13.26
MIPI_DPHY_DSI_TX_D1N: J13.21
MIPI_DPHY_DSI_TX_D1P: J13.20
MIPI_DPHY_DSI_TX_D2N: J13.18
MIPI_DPHY_DSI_TX_D2P: J13.17
MIPI_DPHY_DSI_TX_D3N: J13.30
MIPI_DPHY_DSI_TX_D3P: J13.29
ON/OFF: C30.1 D13.2 R31.1 SW3.2(B1)
PWM0_CH0_M0_IR: R21.2 R26.1
PWR_ON: Q12.3(DRAIN) R31.2
RECOVERY: C27.1 D12.2 R30.1 SW2.2(B1)
RECOVERY_KEY: R30.2
RTC_32K_IN: R29.2
RTC_INT: D18.2 R156.2
SDMMC0_CLK: R20.1
SDMMC0_CMD: R19.1
SDMMC0_D0: R23.1
SDMMC0_D1: R24.1
SDMMC0_D2: R17.1
SDMMC0_D3: R18.1
SDMMC0_DETN: R25.1
SUB1: C105.1 D23.2 J10.A8(SUB1) R119.1 R123.1
SUB2: C106.1 D24.2 J10.B8(SUB2) R122.1 R124.1
TYPEC_CC1: C96.1 D21.2 J10.A5(CC1) U11.10(CC1_1) U11.11(CC1_2)
TYPEC_CC2: C95.1 D22.2 J10.B5(CC2) U11.1(CC2) U11.14(CC2_2)
TYPEC_DM: D20.2 J10.A7(DN1) J10.B7(DN2) R108.1
TYPEC_DP: D19.2 J10.A6(DP1) J10.B6(DP2) R107.1
TYPEC_DPTX_AUX_PUPDCTL1: R119.2
TYPEC_DPTX_AUX_PUPDCTL2: R122.2
TYPEC_SSRXN1: J10.B10(SSRXN1) R113.1 U16.5(D2-) U16.6(NC4)
TYPEC_SSRXN2: J10.A10(SSRXN2) R117.1 U14.5(D2-) U14.6(NC4)
TYPEC_SSRXP1: J10.B11(SSRXP1) R112.1 U16.4(D2+) U16.7(NC3)
TYPEC_SSRXP2: J10.A11(SSRXP2) R114.1 U14.4(D2+) U14.7(NC3)
TYPEC_SSTXN1: C100.1 J10.A3(SSTXN1) U16.1(D1+) U16.10(NC1)
TYPEC_SSTXN2: C102.1 J10.B3(SSTXN2) U14.1(D1+) U14.10(NC1)
TYPEC_SSTXP1: C99.1 J10.A2(SSTXP1) U16.2(D1-) U16.9(NC2)
TYPEC_SSTXP2: C101.1 J10.B2(SSTXP2) U14.2(D1-) U14.9(NC2)
TYPEC_VBUS_EN: R118.1
USB2_OTG0_DM: R108.2
USB2_OTG0_DP: R107.2
USB2_OTG0_ID: R104.2
USB2_OTG0_VBUSDET: R103.2
USB2_OTG1_DM: R132.1
USB2_OTG1_DP: R131.1
USB2_OTG1_ID: R137.2
USB2_OTG1_VBUSDET: R136.2
USB3_OTG0_SSRX1N: R113.2
USB3_OTG0_SSRX1P: R112.2
USB3_OTG0_SSRX2N: R117.2
USB3_OTG0_SSRX2P: R114.2
USB3_OTG0_SSTX1N: C100.2
USB3_OTG0_SSTX1P: C99.2
USB3_OTG0_SSTX2N: C102.2
USB3_OTG0_SSTX2P: C101.2
USB3_OTG1_SSRXN: R110.2
USB3_OTG1_SSRXP: R111.2
USB3_OTG1_SSTXN: C97.2
USB3_OTG1_SSTXP: C98.2
USB20_DM2: J11.11(D-) R115.1 U15.2(D1-) U15.9(NC2)
USB20_DP2: J11.12(D+) R116.1 U15.1(D1+) U15.10(NC1)
USB20_HOST_PWR_EN: R134.1
USB30_DM: J11.2(D-) R105.1 U17.5(D2-) U17.6(NC4)
USB30_DP: J11.3(D+) R106.1 U17.4(D2+) U17.7(NC3)
USB30_HOST_PWR_EN: R121.1
USB30_RXN: J11.5(RX-) R110.1 U17.1(D1+) U17.10(NC1)
USB30_RXP: J11.6(RX+) R111.1 U17.2(D1-) U17.9(NC2)
USB30_TXN: C97.1 J11.8(TX-) U15.4(D2+) U15.7(NC3)
USB30_TXP: C98.1 J11.9(TX+) U15.5(D2-) U15.6(NC4)
USB_HUB_1V8: C123.1 C124.1 C125.1 C126.1 C127.1 U19.6(VD18_1) U19.21(VD_PLL) U19.25(VD18_O) U19.28(VD18_2)
USB_HUB_3V3: C109.1 C110.1 C116.1 C117.1 C118.1 C120.1 C121.1 R127.2 R128.2 R129.2 R130.2 U19.15(VD33_1) U19.20(VD33_2) U19.26(VD33_3) U19.31(VD33_4) U19.36(VD33_5) U19.42(VD33_6) U19.43(OVCJ[5]) U19.45(OVCJ[1])
USB_HUB_3V3_OUT: C114.1 C115.1 R128.1 U19.9(VD33_O)
USB_HUB_5V0: C112.1 C113.1 R126.2 U19.8(VDD5)
USB_HUB_DM1: R105.2 U19.18(DM1)
USB_HUB_DM2: R115.2 U19.16(DM2)
USB_HUB_DM3: J12.2(D-) U18.2(D1-) U18.9(NC2) U19.13(DM3)
USB_HUB_DM4: J12.8(D-) U18.5(D2-) U18.6(NC4) U19.11(DM4)
USB_HUB_DM5: U19.32(DM5) ; also on sheet 4
USB_HUB_DM6: U19.34(DM6) ; also on sheet 6
USB_HUB_DP1: R106.2 U19.19(DP1)
USB_HUB_DP2: R116.2 U19.17(DP2)
USB_HUB_DP3: J12.3(D+) U18.1(D1+) U18.10(NC1) U19.14(DP3)
USB_HUB_DP4: J12.9(D+) U18.4(D2+) U18.7(NC3) U19.12(DP4)
USB_HUB_DP5: U19.33(DP5) ; also on sheet 4
USB_HUB_DP6: U19.35(DP6) ; also on sheet 6
N16965184: D8.2 J4.1(DAT2) R17.2
N16965201: D7.2 J4.2(CD/DAT3) R18.2
N16965205: D6.2 J4.3(CMD) R19.2
N16965209: D5.2 J4.5(CLK) R20.2
N16965213: D4.2 J4.7(DAT0) R23.2
N16965217: D3.2 J4.8(DAT1) R24.2
N16965221: D2.2 J4.9(CD) R25.2
N16966392: R26.2 U4.3(OUT)
N16966399: C22.1 C23.1 R22.2 U4.2(VCC)
N16985416: J10.1(SH1) J10.2(SH2) J10.3(SH3) J10.4(SH4) L11.1
N16990092: R120.1 U12.3(ISET)
N16998300: Q10.2(SOURCE) R150.2 R152.2
N17003573: Q18.1(GATE) Q19.1(GATE) Q20.1(GATE) Q21.1(GATE) R164.2 R165.1
N17013167: Q8.1(GATE) Q9.3(DRAIN) R142.2
N17014356: Q9.1(GATE) R149.1 R151.1
N17029455: C148.1 R153.2 U24.4(EN) U25.4(EN)
N17029502: R154.1 U24.3(ISET)
N17029521: R161.1 U25.3(ISET)
N17112236: C29.1 U5.2(OSCO) Y1.2
N17112246: C28.1 U5.1(OSCI) Y1.1
N17112592: R28.2 R29.1 U5.7(CLKOUT)
N17115633: Q3.3(DRAIN) Q12.1(GATE) R241.2
N17117541: R118.2 U12.4(EN)
N17149641: R121.2 U13.4(EN)
N17149662: R125.1 U13.3(ISET)
N17150434: J11.19(SH1) J11.20(SH2) J11.21(SH1) J11.22(SH2) L10.1
N17156781: R133.1 U19.27(REXT)
N17157129: C131.1 U19.22(XIN) Y4.3
N17157136: C130.1 U19.23(XOUT) Y4.1
N17158781: C122.1 R130.1 U19.41(VBUSM)
N17159812: R129.1 U19.40(XRSTJ)
N17161099: R131.2 U19.30(DPU)
N17161102: R132.2 U19.29(DMU)
N17163205: J12.5(SH1) J12.6(SH2) J12.11(SH1) J12.12(SH2) L12.1
N17166688: C132.1 R134.2 U20.4(EN)
N17166697: R135.1 U20.3(ISET)
N17318769: J33.G1(20) J33.G2(21) J33.G3(22) J33.G4(23) L27.2
N17319613: Q21.3(DRAIN) R233.2 R234.2
N17319615: Q20.3(DRAIN) R231.2 R232.2
N17319817: Q19.3(DRAIN) R229.2 R230.2
N17319825: Q18.3(DRAIN) R227.2 R228.2

Not connected (* = marked no-connect by the designer): J11 14(NC1)* 15(NC2)* 17(NC4)* 18(NC5)*; J13 14*; U19 1(DRV)* 2(TESTJ)* 3(LED[1])* 4(LED[2])* 5(LED[3])* 7(LED[4])* 37(DM7)* 38(DP7)* 44(PWRJ[1])* 46(LED[7])* 47(LED[6])* 48(LED[5])*

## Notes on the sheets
sheet 8
- HDMI2.1
- DSI PORT
- GPIO0_D0
- GPIO0_D1
- PWM1_CH2_M1
- GPIO1_C1
- DSI PWR
- GPIO0_B6
- GPIO4_C6
sheet 9
- SD CARD
- IR接收
- KLXES15AAA1*7
- RTC电源插座，支持断电保存时间
- 按键
- 支持关机保持时间
- 支持RTC ALARM开机
sheet 10
- TYPE-C3.2
- USB2.0 USB3.0 HOST
- USB3.0 HOST
- GPIO0_B4
- GPIO0_B5
- GPIO4_C4
- GPIO1_C4
- GPIO4_C5
- USB2.0 HUB
- USB2.0 HOST
- 电流流向
- GPIO1_C6
